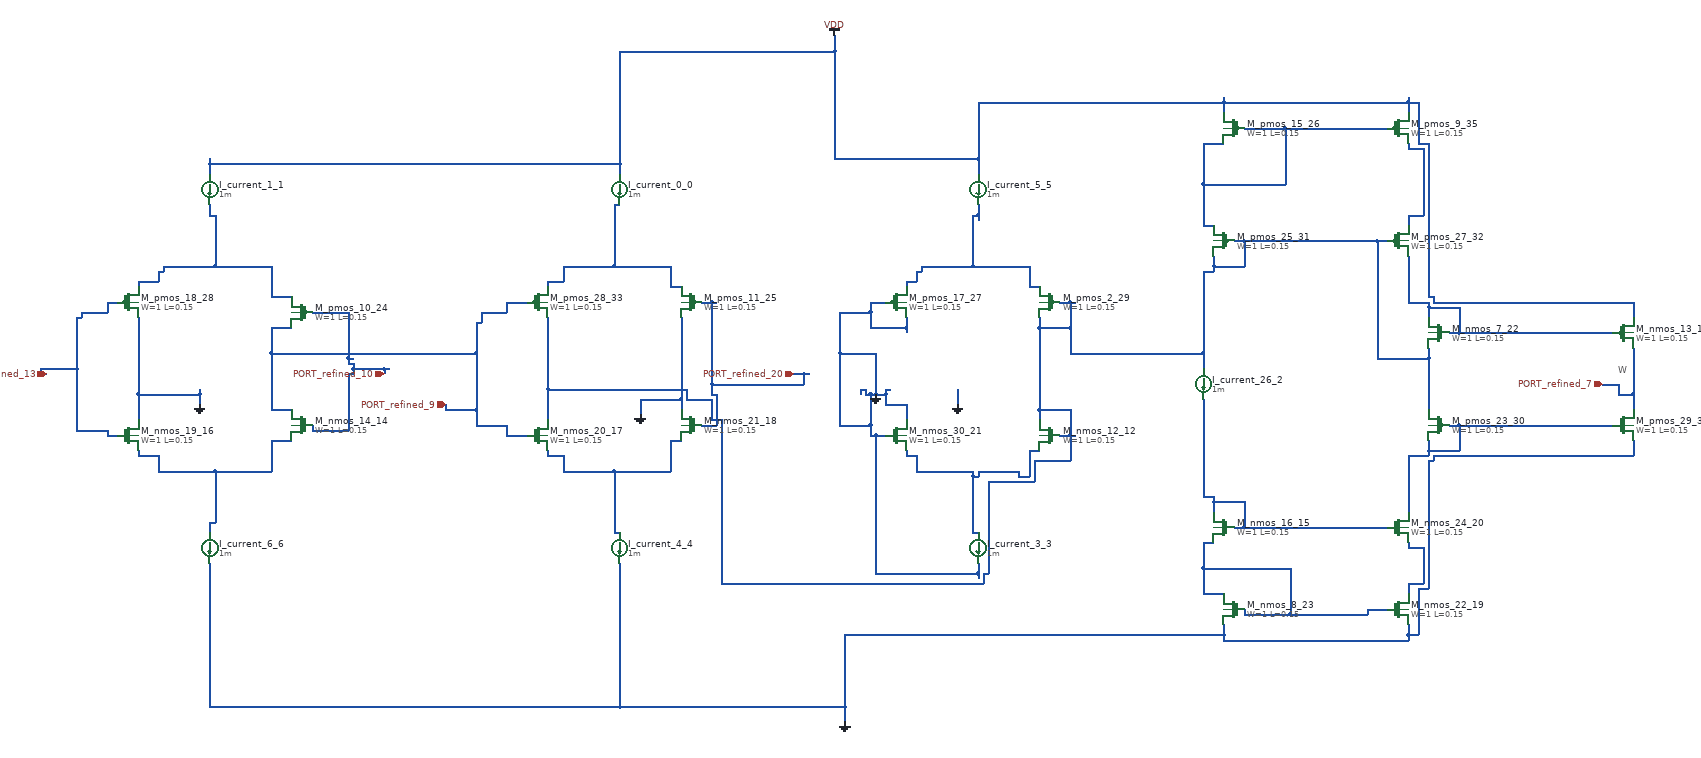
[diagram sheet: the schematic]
v {xschem version=3.4.8 file_version=1.2}
G {}
K {}
V {}
S {}
E {}
C {devices/isource.sym} 1160 500 0 0 {name="I_current_0_0" value=1m}
C {devices/isource.sym} 360 500 0 0 {name="I_current_1_1" value=1m}
C {devices/isource.sym} 2300 880 0 0 {name="I_current_26_2" value=1m}
C {devices/isource.sym} 1860 1200 0 0 {name="I_current_3_3" value=1m}
C {devices/isource.sym} 1160 1200 0 0 {name="I_current_4_4" value=1m}
C {devices/isource.sym} 1860 500 0 0 {name="I_current_5_5" value=1m}
C {devices/isource.sym} 360 1200 0 0 {name="I_current_6_6" value=1m}
C {devices/gnd.sym} 340 920 0 0 {name="l_gnd_31_7" lab="GND"}
C {devices/gnd.sym} 1820 920 0 0 {name="l_gnd_32_8" lab="GND"}
C {devices/gnd.sym} 1200 940 0 0 {name="l_gnd_34_9" lab="GND"}
C {devices/gnd.sym} 1600 1540 0 0 {name="l_gnd_38_10" lab="GND"}
C {devices/gnd.sym} 1660 900 0 0 {name="l_gnd_50_11" lab="GND"}
C {sky130_fd_pr/nfet3_01v8.sym} 2000 980 0 1 {name="M_nmos_12_12"
W=1
L=0.15
body=GND
nf=1
mult=1
ad="expr('int((@nf + 1)/2) * @W / @nf * 0.29')"
pd="expr('2*int((@nf + 1)/2) * (@W / @nf + 0.29)')"
as="expr('int((@nf + 2)/2) * @W / @nf * 0.29')"
ps="expr('2*int((@nf + 2)/2) * (@W / @nf + 0.29)')"
nrd="expr('0.29 / @W ')" nrs="expr('0.29 / @W ')"
sa=0 sb=0 sd=0
model=nfet_01v8
spiceprefix=X
}
C {sky130_fd_pr/pfet3_01v8.sym} 3120 780 0 0 {name="M_nmos_13_13"
W=1
L=0.15
body=VDD
nf=1
mult=1
ad="expr('int((@nf + 1)/2) * @W / @nf * 0.29')"
pd="expr('2*int((@nf + 1)/2) * (@W / @nf + 0.29)')"
as="expr('int((@nf + 2)/2) * @W / @nf * 0.29')"
ps="expr('2*int((@nf + 2)/2) * (@W / @nf + 0.29)')"
nrd="expr('0.29 / @W ')" nrs="expr('0.29 / @W ')"
sa=0 sb=0 sd=0
model=pfet_01v8
spiceprefix=X
}
C {sky130_fd_pr/nfet3_01v8.sym} 540 960 0 1 {name="M_nmos_14_14"
W=1
L=0.15
body=GND
nf=1
mult=1
ad="expr('int((@nf + 1)/2) * @W / @nf * 0.29')"
pd="expr('2*int((@nf + 1)/2) * (@W / @nf + 0.29)')"
as="expr('int((@nf + 2)/2) * @W / @nf * 0.29')"
ps="expr('2*int((@nf + 2)/2) * (@W / @nf + 0.29)')"
nrd="expr('0.29 / @W ')" nrs="expr('0.29 / @W ')"
sa=0 sb=0 sd=0
model=nfet_01v8
spiceprefix=X
}
C {sky130_fd_pr/nfet3_01v8.sym} 2340 1160 0 1 {name="M_nmos_16_15"
W=1
L=0.15
body=GND
nf=1
mult=1
ad="expr('int((@nf + 1)/2) * @W / @nf * 0.29')"
pd="expr('2*int((@nf + 1)/2) * (@W / @nf + 0.29)')"
as="expr('int((@nf + 2)/2) * @W / @nf * 0.29')"
ps="expr('2*int((@nf + 2)/2) * (@W / @nf + 0.29)')"
nrd="expr('0.29 / @W ')" nrs="expr('0.29 / @W ')"
sa=0 sb=0 sd=0
model=nfet_01v8
spiceprefix=X
}
C {sky130_fd_pr/nfet3_01v8.sym} 200 980 0 0 {name="M_nmos_19_16"
W=1
L=0.15
body=GND
nf=1
mult=1
ad="expr('int((@nf + 1)/2) * @W / @nf * 0.29')"
pd="expr('2*int((@nf + 1)/2) * (@W / @nf + 0.29)')"
as="expr('int((@nf + 2)/2) * @W / @nf * 0.29')"
ps="expr('2*int((@nf + 2)/2) * (@W / @nf + 0.29)')"
nrd="expr('0.29 / @W ')" nrs="expr('0.29 / @W ')"
sa=0 sb=0 sd=0
model=nfet_01v8
spiceprefix=X
}
C {sky130_fd_pr/nfet3_01v8.sym} 1000 980 0 0 {name="M_nmos_20_17"
W=1
L=0.15
body=GND
nf=1
mult=1
ad="expr('int((@nf + 1)/2) * @W / @nf * 0.29')"
pd="expr('2*int((@nf + 1)/2) * (@W / @nf + 0.29)')"
as="expr('int((@nf + 2)/2) * @W / @nf * 0.29')"
ps="expr('2*int((@nf + 2)/2) * (@W / @nf + 0.29)')"
nrd="expr('0.29 / @W ')" nrs="expr('0.29 / @W ')"
sa=0 sb=0 sd=0
model=nfet_01v8
spiceprefix=X
}
C {sky130_fd_pr/nfet3_01v8.sym} 1300 960 2 0 {name="M_nmos_21_18"
W=1
L=0.15
body=GND
nf=1
mult=1
ad="expr('int((@nf + 1)/2) * @W / @nf * 0.29')"
pd="expr('2*int((@nf + 1)/2) * (@W / @nf + 0.29)')"
as="expr('int((@nf + 2)/2) * @W / @nf * 0.29')"
ps="expr('2*int((@nf + 2)/2) * (@W / @nf + 0.29)')"
nrd="expr('0.29 / @W ')" nrs="expr('0.29 / @W ')"
sa=0 sb=0 sd=0
model=nfet_01v8
spiceprefix=X
}
C {sky130_fd_pr/nfet3_01v8.sym} 2680 1320 0 0 {name="M_nmos_22_19"
W=1
L=0.15
body=GND
nf=1
mult=1
ad="expr('int((@nf + 1)/2) * @W / @nf * 0.29')"
pd="expr('2*int((@nf + 1)/2) * (@W / @nf + 0.29)')"
as="expr('int((@nf + 2)/2) * @W / @nf * 0.29')"
ps="expr('2*int((@nf + 2)/2) * (@W / @nf + 0.29)')"
nrd="expr('0.29 / @W ')" nrs="expr('0.29 / @W ')"
sa=0 sb=0 sd=0
model=nfet_01v8
spiceprefix=X
}
C {sky130_fd_pr/nfet3_01v8.sym} 2680 1160 0 0 {name="M_nmos_24_20"
W=1
L=0.15
body=GND
nf=1
mult=1
ad="expr('int((@nf + 1)/2) * @W / @nf * 0.29')"
pd="expr('2*int((@nf + 1)/2) * (@W / @nf + 0.29)')"
as="expr('int((@nf + 2)/2) * @W / @nf * 0.29')"
ps="expr('2*int((@nf + 2)/2) * (@W / @nf + 0.29)')"
nrd="expr('0.29 / @W ')" nrs="expr('0.29 / @W ')"
sa=0 sb=0 sd=0
model=nfet_01v8
spiceprefix=X
}
C {sky130_fd_pr/nfet3_01v8.sym} 1700 980 2 1 {name="M_nmos_30_21"
W=1
L=0.15
body=GND
nf=1
mult=1
ad="expr('int((@nf + 1)/2) * @W / @nf * 0.29')"
pd="expr('2*int((@nf + 1)/2) * (@W / @nf + 0.29)')"
as="expr('int((@nf + 2)/2) * @W / @nf * 0.29')"
ps="expr('2*int((@nf + 2)/2) * (@W / @nf + 0.29)')"
nrd="expr('0.29 / @W ')" nrs="expr('0.29 / @W ')"
sa=0 sb=0 sd=0
model=nfet_01v8
spiceprefix=X
}
C {sky130_fd_pr/nfet3_01v8.sym} 2760 780 0 1 {name="M_nmos_7_22"
W=1
L=0.15
body=GND
nf=1
mult=1
ad="expr('int((@nf + 1)/2) * @W / @nf * 0.29')"
pd="expr('2*int((@nf + 1)/2) * (@W / @nf + 0.29)')"
as="expr('int((@nf + 2)/2) * @W / @nf * 0.29')"
ps="expr('2*int((@nf + 2)/2) * (@W / @nf + 0.29)')"
nrd="expr('0.29 / @W ')" nrs="expr('0.29 / @W ')"
sa=0 sb=0 sd=0
model=nfet_01v8
spiceprefix=X
}
C {sky130_fd_pr/nfet3_01v8.sym} 2360 1320 0 1 {name="M_nmos_8_23"
W=1
L=0.15
body=GND
nf=1
mult=1
ad="expr('int((@nf + 1)/2) * @W / @nf * 0.29')"
pd="expr('2*int((@nf + 1)/2) * (@W / @nf + 0.29)')"
as="expr('int((@nf + 2)/2) * @W / @nf * 0.29')"
ps="expr('2*int((@nf + 2)/2) * (@W / @nf + 0.29)')"
nrd="expr('0.29 / @W ')" nrs="expr('0.29 / @W ')"
sa=0 sb=0 sd=0
model=nfet_01v8
spiceprefix=X
}
C {sky130_fd_pr/pfet3_01v8.sym} 540 740 0 1 {name="M_pmos_10_24"
W=1
L=0.15
body=VDD
nf=1
mult=1
ad="expr('int((@nf + 1)/2) * @W / @nf * 0.29')"
pd="expr('2*int((@nf + 1)/2) * (@W / @nf + 0.29)')"
as="expr('int((@nf + 2)/2) * @W / @nf * 0.29')"
ps="expr('2*int((@nf + 2)/2) * (@W / @nf + 0.29)')"
nrd="expr('0.29 / @W ')" nrs="expr('0.29 / @W ')"
sa=0 sb=0 sd=0
model=pfet_01v8
spiceprefix=X
}
C {sky130_fd_pr/pfet3_01v8.sym} 1300 720 0 1 {name="M_pmos_11_25"
W=1
L=0.15
body=VDD
nf=1
mult=1
ad="expr('int((@nf + 1)/2) * @W / @nf * 0.29')"
pd="expr('2*int((@nf + 1)/2) * (@W / @nf + 0.29)')"
as="expr('int((@nf + 2)/2) * @W / @nf * 0.29')"
ps="expr('2*int((@nf + 2)/2) * (@W / @nf + 0.29)')"
nrd="expr('0.29 / @W ')" nrs="expr('0.29 / @W ')"
sa=0 sb=0 sd=0
model=pfet_01v8
spiceprefix=X
}
C {sky130_fd_pr/pfet3_01v8.sym} 2360 380 0 1 {name="M_pmos_15_26"
W=1
L=0.15
body=VDD
nf=1
mult=1
ad="expr('int((@nf + 1)/2) * @W / @nf * 0.29')"
pd="expr('2*int((@nf + 1)/2) * (@W / @nf + 0.29)')"
as="expr('int((@nf + 2)/2) * @W / @nf * 0.29')"
ps="expr('2*int((@nf + 2)/2) * (@W / @nf + 0.29)')"
nrd="expr('0.29 / @W ')" nrs="expr('0.29 / @W ')"
sa=0 sb=0 sd=0
model=pfet_01v8
spiceprefix=X
}
C {sky130_fd_pr/pfet3_01v8.sym} 1700 720 0 0 {name="M_pmos_17_27"
W=1
L=0.15
body=VDD
nf=1
mult=1
ad="expr('int((@nf + 1)/2) * @W / @nf * 0.29')"
pd="expr('2*int((@nf + 1)/2) * (@W / @nf + 0.29)')"
as="expr('int((@nf + 2)/2) * @W / @nf * 0.29')"
ps="expr('2*int((@nf + 2)/2) * (@W / @nf + 0.29)')"
nrd="expr('0.29 / @W ')" nrs="expr('0.29 / @W ')"
sa=0 sb=0 sd=0
model=pfet_01v8
spiceprefix=X
}
C {sky130_fd_pr/pfet3_01v8.sym} 200 720 0 0 {name="M_pmos_18_28"
W=1
L=0.15
body=VDD
nf=1
mult=1
ad="expr('int((@nf + 1)/2) * @W / @nf * 0.29')"
pd="expr('2*int((@nf + 1)/2) * (@W / @nf + 0.29)')"
as="expr('int((@nf + 2)/2) * @W / @nf * 0.29')"
ps="expr('2*int((@nf + 2)/2) * (@W / @nf + 0.29)')"
nrd="expr('0.29 / @W ')" nrs="expr('0.29 / @W ')"
sa=0 sb=0 sd=0
model=pfet_01v8
spiceprefix=X
}
C {sky130_fd_pr/pfet3_01v8.sym} 2000 720 0 1 {name="M_pmos_2_29"
W=1
L=0.15
body=VDD
nf=1
mult=1
ad="expr('int((@nf + 1)/2) * @W / @nf * 0.29')"
pd="expr('2*int((@nf + 1)/2) * (@W / @nf + 0.29)')"
as="expr('int((@nf + 2)/2) * @W / @nf * 0.29')"
ps="expr('2*int((@nf + 2)/2) * (@W / @nf + 0.29)')"
nrd="expr('0.29 / @W ')" nrs="expr('0.29 / @W ')"
sa=0 sb=0 sd=0
model=pfet_01v8
spiceprefix=X
}
C {sky130_fd_pr/pfet3_01v8.sym} 2760 960 0 1 {name="M_pmos_23_30"
W=1
L=0.15
body=VDD
nf=1
mult=1
ad="expr('int((@nf + 1)/2) * @W / @nf * 0.29')"
pd="expr('2*int((@nf + 1)/2) * (@W / @nf + 0.29)')"
as="expr('int((@nf + 2)/2) * @W / @nf * 0.29')"
ps="expr('2*int((@nf + 2)/2) * (@W / @nf + 0.29)')"
nrd="expr('0.29 / @W ')" nrs="expr('0.29 / @W ')"
sa=0 sb=0 sd=0
model=pfet_01v8
spiceprefix=X
}
C {sky130_fd_pr/pfet3_01v8.sym} 2340 600 0 1 {name="M_pmos_25_31"
W=1
L=0.15
body=VDD
nf=1
mult=1
ad="expr('int((@nf + 1)/2) * @W / @nf * 0.29')"
pd="expr('2*int((@nf + 1)/2) * (@W / @nf + 0.29)')"
as="expr('int((@nf + 2)/2) * @W / @nf * 0.29')"
ps="expr('2*int((@nf + 2)/2) * (@W / @nf + 0.29)')"
nrd="expr('0.29 / @W ')" nrs="expr('0.29 / @W ')"
sa=0 sb=0 sd=0
model=pfet_01v8
spiceprefix=X
}
C {sky130_fd_pr/pfet3_01v8.sym} 2680 600 0 0 {name="M_pmos_27_32"
W=1
L=0.15
body=VDD
nf=1
mult=1
ad="expr('int((@nf + 1)/2) * @W / @nf * 0.29')"
pd="expr('2*int((@nf + 1)/2) * (@W / @nf + 0.29)')"
as="expr('int((@nf + 2)/2) * @W / @nf * 0.29')"
ps="expr('2*int((@nf + 2)/2) * (@W / @nf + 0.29)')"
nrd="expr('0.29 / @W ')" nrs="expr('0.29 / @W ')"
sa=0 sb=0 sd=0
model=pfet_01v8
spiceprefix=X
}
C {sky130_fd_pr/pfet3_01v8.sym} 1000 720 0 0 {name="M_pmos_28_33"
W=1
L=0.15
body=VDD
nf=1
mult=1
ad="expr('int((@nf + 1)/2) * @W / @nf * 0.29')"
pd="expr('2*int((@nf + 1)/2) * (@W / @nf + 0.29)')"
as="expr('int((@nf + 2)/2) * @W / @nf * 0.29')"
ps="expr('2*int((@nf + 2)/2) * (@W / @nf + 0.29)')"
nrd="expr('0.29 / @W ')" nrs="expr('0.29 / @W ')"
sa=0 sb=0 sd=0
model=pfet_01v8
spiceprefix=X
}
C {sky130_fd_pr/nfet3_01v8.sym} 3120 960 0 0 {name="M_pmos_29_34"
W=1
L=0.15
body=GND
nf=1
mult=1
ad="expr('int((@nf + 1)/2) * @W / @nf * 0.29')"
pd="expr('2*int((@nf + 1)/2) * (@W / @nf + 0.29)')"
as="expr('int((@nf + 2)/2) * @W / @nf * 0.29')"
ps="expr('2*int((@nf + 2)/2) * (@W / @nf + 0.29)')"
nrd="expr('0.29 / @W ')" nrs="expr('0.29 / @W ')"
sa=0 sb=0 sd=0
model=nfet_01v8
spiceprefix=X
}
C {sky130_fd_pr/pfet3_01v8.sym} 2680 380 0 0 {name="M_pmos_9_35"
W=1
L=0.15
body=VDD
nf=1
mult=1
ad="expr('int((@nf + 1)/2) * @W / @nf * 0.29')"
pd="expr('2*int((@nf + 1)/2) * (@W / @nf + 0.29)')"
as="expr('int((@nf + 2)/2) * @W / @nf * 0.29')"
ps="expr('2*int((@nf + 2)/2) * (@W / @nf + 0.29)')"
nrd="expr('0.29 / @W ')" nrs="expr('0.29 / @W ')"
sa=0 sb=0 sd=0
model=pfet_01v8
spiceprefix=X
}
C {devices/ipin.sym} 820 920 0 0 {name="p_port_33_36" lab="PORT_refined_9"}
C {devices/ipin.sym} 40 860 0 0 {name="p_port_35_37" lab="PORT_refined_13"}
C {devices/ipin.sym} 700 860 0 0 {name="p_port_36_38" lab="PORT_refined_10"}
C {devices/ipin.sym} 1500 860 0 0 {name="p_port_37_39" lab="PORT_refined_20"}
C {devices/ipin.sym} 3080 880 0 0 {name="p_port_40_40" lab="PORT_refined_7"}
T {W} 3110 840 0 0 0.25 0.25 {}
C {devices/vdd.sym} 1580 200 0 0 {name="l_vdd_41_41" lab="VDD"}
N 1260 690 1280 690 {}
N 1020 680 1050 680 {}
N 1050 650 1150 650 {}
N 1150 650 1260 650 {}
N 1150 530 1160 530 {}
N 1020 690 1020 680 {}
N 1050 680 1050 650 {}
N 1150 650 1150 530 {}
N 1260 690 1260 650 {}
N 2750 720 3140 720 {}
N 2740 710 2750 710 {}
N 360 450 1160 450 {}
N 1580 440 1860 440 {}
N 2720 410 2740 410 {}
N 1860 330 2340 330 {}
N 2340 330 2700 330 {}
N 2700 330 2720 330 {}
N 1160 230 1580 230 {}
N 360 470 360 450 {}
N 360 450 360 440 {}
N 1160 470 1160 450 {}
N 1160 450 1160 230 {}
N 1580 440 1580 230 {}
N 1580 230 1580 200 {}
N 1860 470 1860 440 {}
N 1860 440 1860 330 {}
N 2340 350 2340 330 {}
N 2340 330 2340 320 {}
N 2700 350 2700 330 {}
N 2700 330 2700 320 {}
N 2720 410 2720 330 {}
N 2740 710 2740 410 {}
N 2750 720 2750 710 {}
N 3140 750 3140 720 {}
N 560 970 630 970 {}
N 630 860 640 860 {}
N 640 850 700 850 {}
N 700 850 710 850 {}
N 630 840 640 840 {}
N 630 830 640 830 {}
N 560 740 630 740 {}
N 560 970 560 960 {}
N 630 970 630 860 {}
N 630 840 630 830 {}
N 630 830 630 740 {}
N 640 860 640 850 {}
N 640 850 640 840 {}
N 700 860 700 850 {}
N 2380 1330 2470 1330 {}
N 2470 1330 2620 1330 {}
N 2620 1320 2660 1320 {}
N 2300 1290 2340 1290 {}
N 2300 1240 2470 1240 {}
N 2300 1190 2320 1190 {}
N 2300 1290 2300 1240 {}
N 2300 1240 2300 1190 {}
N 2380 1330 2380 1320 {}
N 2470 1330 2470 1240 {}
N 2620 1330 2620 1320 {}
N 2360 1160 2380 1160 {}
N 2380 1160 2660 1160 {}
N 2320 1110 2380 1110 {}
N 2300 1100 2320 1100 {}
N 2300 1100 2300 910 {}
N 2320 1130 2320 1110 {}
N 2320 1110 2320 1100 {}
N 2380 1160 2380 1110 {}
N 160 980 180 980 {}
N 100 970 160 970 {}
N 30 860 40 860 {}
N 30 850 100 850 {}
N 100 750 110 750 {}
N 110 740 160 740 {}
N 160 720 180 720 {}
N 30 860 30 850 {}
N 100 970 100 850 {}
N 100 850 100 750 {}
N 110 750 110 740 {}
N 160 980 160 970 {}
N 160 740 160 720 {}
N 1150 1170 1160 1170 {}
N 1050 1050 1150 1050 {}
N 1150 1050 1260 1050 {}
N 1020 1020 1050 1020 {}
N 1260 990 1280 990 {}
N 1020 1020 1020 1010 {}
N 1050 1050 1050 1020 {}
N 1150 1170 1150 1050 {}
N 1260 1050 1260 990 {}
N 1360 1270 1870 1270 {}
N 1870 1250 1880 1250 {}
N 1880 1070 1970 1070 {}
N 1970 1030 2040 1030 {}
N 2020 980 2040 980 {}
N 2040 980 2050 980 {}
N 1340 950 1360 950 {}
N 1980 930 2040 930 {}
N 1290 910 1340 910 {}
N 1020 890 1290 890 {}
N 2640 830 2740 830 {}
N 2040 820 2300 820 {}
N 1980 770 2040 770 {}
N 2020 720 2040 720 {}
N 2040 720 2050 720 {}
N 2300 660 2320 660 {}
N 2320 650 2380 650 {}
N 2360 600 2380 600 {}
N 2380 600 2640 600 {}
N 2640 600 2660 600 {}
N 1020 950 1020 890 {}
N 1020 890 1020 750 {}
N 1290 910 1290 890 {}
N 1340 950 1340 910 {}
N 1360 1270 1360 950 {}
N 1870 1270 1870 1250 {}
N 1880 1250 1880 1070 {}
N 1970 1070 1970 1030 {}
N 1980 950 1980 930 {}
N 1980 930 1980 770 {}
N 1980 770 1980 750 {}
N 2040 1030 2040 980 {}
N 2040 980 2040 930 {}
N 2040 820 2040 770 {}
N 2040 770 2040 720 {}
N 2300 850 2300 820 {}
N 2300 820 2300 660 {}
N 2320 660 2320 650 {}
N 2320 650 2320 630 {}
N 2380 650 2380 600 {}
N 2640 830 2640 600 {}
N 2740 930 2740 830 {}
N 2740 830 2740 810 {}
N 2700 1270 2730 1270 {}
N 2700 1200 2730 1200 {}
N 2700 1290 2700 1270 {}
N 2700 1200 2700 1190 {}
N 2730 1270 2730 1200 {}
N 2700 1020 2740 1020 {}
N 2740 1010 2800 1010 {}
N 2780 960 2800 960 {}
N 2800 960 3100 960 {}
N 2700 1130 2700 1020 {}
N 2740 1020 2740 1010 {}
N 2740 1010 2740 990 {}
N 2800 1010 2800 960 {}
N 2300 570 2320 570 {}
N 2300 490 2460 490 {}
N 2300 410 2340 410 {}
N 2380 380 2460 380 {}
N 2460 380 2660 380 {}
N 2300 570 2300 490 {}
N 2300 490 2300 410 {}
N 2460 490 2460 380 {}
N 2700 550 2730 550 {}
N 2700 420 2730 420 {}
N 2700 570 2700 550 {}
N 2700 420 2700 410 {}
N 2730 550 2730 420 {}
N 1960 690 1980 690 {}
N 1720 680 1740 680 {}
N 1740 660 1750 660 {}
N 1750 650 1850 650 {}
N 1850 650 1960 650 {}
N 1850 550 1860 550 {}
N 1720 690 1720 680 {}
N 1740 680 1740 660 {}
N 1750 660 1750 650 {}
N 1850 650 1850 550 {}
N 1860 560 1860 550 {}
N 1860 550 1860 530 {}
N 1960 690 1960 650 {}
N 1320 960 1350 960 {}
N 1340 900 1350 900 {}
N 1340 880 1520 880 {}
N 1500 860 1520 860 {}
N 1520 860 1530 860 {}
N 1320 720 1340 720 {}
N 1340 720 1350 720 {}
N 1340 900 1340 880 {}
N 1340 880 1340 720 {}
N 1350 960 1350 900 {}
N 1520 880 1520 860 {}
N 360 1510 1160 1510 {}
N 1160 1510 1600 1510 {}
N 2340 1380 2700 1380 {}
N 1600 1370 2340 1370 {}
N 2700 1370 2720 1370 {}
N 2720 1280 2740 1280 {}
N 1660 1250 1860 1250 {}
N 2740 1030 2750 1030 {}
N 2750 1020 3140 1020 {}
N 1650 980 1660 980 {}
N 1660 980 1680 980 {}
N 1590 960 1650 960 {}
N 1680 920 1720 920 {}
N 1200 910 1280 910 {}
N 220 900 340 900 {}
N 1640 900 1650 900 {}
N 1650 900 1660 900 {}
N 1660 900 1680 900 {}
N 1630 890 1640 890 {}
N 1680 890 1690 890 {}
N 1590 820 1660 820 {}
N 1650 770 1720 770 {}
N 1590 740 1650 740 {}
N 1650 720 1680 720 {}
N 220 950 220 900 {}
N 220 900 220 750 {}
N 340 920 340 900 {}
N 340 900 340 890 {}
N 360 1510 360 1230 {}
N 1160 1510 1160 1230 {}
N 1200 940 1200 910 {}
N 1280 930 1280 910 {}
N 1280 910 1280 750 {}
N 1590 960 1590 820 {}
N 1590 820 1590 740 {}
N 1600 1540 1600 1510 {}
N 1600 1510 1600 1370 {}
N 1630 900 1630 890 {}
N 1640 900 1640 890 {}
N 1650 980 1650 960 {}
N 1650 960 1650 900 {}
N 1650 770 1650 740 {}
N 1650 740 1650 720 {}
N 1660 1250 1660 980 {}
N 1660 900 1660 820 {}
N 1680 920 1680 900 {}
N 1680 900 1680 890 {}
N 1720 950 1720 920 {}
N 1720 780 1720 770 {}
N 1720 770 1720 750 {}
N 1820 920 1820 890 {}
N 1860 1260 1860 1250 {}
N 1860 1250 1860 1230 {}
N 2340 1380 2340 1370 {}
N 2340 1370 2340 1350 {}
N 2700 1380 2700 1370 {}
N 2700 1370 2700 1350 {}
N 2720 1370 2720 1280 {}
N 2740 1280 2740 1030 {}
N 2750 1030 2750 1020 {}
N 3140 1020 3140 990 {}
N 360 1150 370 1150 {}
N 260 1050 370 1050 {}
N 370 1050 480 1050 {}
N 220 1020 260 1020 {}
N 480 990 520 990 {}
N 220 1020 220 1010 {}
N 260 1050 260 1020 {}
N 360 1170 360 1150 {}
N 370 1150 370 1050 {}
N 480 1050 480 990 {}
N 1850 1170 1860 1170 {}
N 1850 1060 1860 1060 {}
N 1940 1060 1960 1060 {}
N 1740 1050 1850 1050 {}
N 1860 1050 1940 1050 {}
N 1720 1020 1740 1020 {}
N 1960 1010 1980 1010 {}
N 1720 1020 1720 1010 {}
N 1740 1050 1740 1020 {}
N 1850 1170 1850 1060 {}
N 1850 1060 1850 1050 {}
N 1860 1060 1860 1050 {}
N 1940 1060 1940 1050 {}
N 1960 1060 1960 1010 {}
N 480 710 520 710 {}
N 220 680 260 680 {}
N 260 660 270 660 {}
N 270 650 370 650 {}
N 370 650 480 650 {}
N 360 550 370 550 {}
N 220 690 220 680 {}
N 260 680 260 660 {}
N 270 660 270 650 {}
N 360 550 360 530 {}
N 370 650 370 550 {}
N 480 710 480 650 {}
N 3110 900 3140 900 {}
N 3080 880 3110 880 {}
N 3110 900 3110 880 {}
N 3140 930 3140 900 {}
N 3140 900 3140 810 {}
N 2780 780 2800 780 {}
N 2800 780 3100 780 {}
N 2740 730 2800 730 {}
N 2700 720 2740 720 {}
N 2700 720 2700 630 {}
N 2740 750 2740 730 {}
N 2740 730 2740 720 {}
N 2800 780 2800 730 {}
N 940 980 980 980 {}
N 880 960 940 960 {}
N 480 930 520 930 {}
N 820 930 880 930 {}
N 480 820 880 820 {}
N 480 770 520 770 {}
N 880 760 890 760 {}
N 890 740 940 740 {}
N 940 720 980 720 {}
N 480 930 480 820 {}
N 480 820 480 770 {}
N 820 930 820 920 {}
N 880 960 880 930 {}
N 880 930 880 820 {}
N 880 820 880 760 {}
N 890 760 890 740 {}
N 940 980 940 960 {}
N 940 740 940 720 {}
